VERSION 5.8 ;
BUSBITCHARS "[]" ;
DIVIDERCHAR "/" ;
CLEARANCEMEASURE EUCLIDEAN ;

SITE coresite_DH_P
    SIZE 0.0450 BY 0.2880 ;
    CLASS CORE ;
    SYMMETRY X Y ;
END coresite_DH_P

SITE coresite_DH_N
    SIZE 0.0450 BY 0.2880 ;
    CLASS CORE ;
    SYMMETRY X Y ;
END coresite_DH_N

SITE coresite
    SIZE 0.0450 BY 0.1440 ;
    CLASS CORE ;
    SYMMETRY X Y ;
END coresite

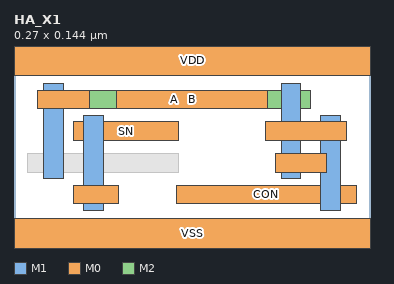
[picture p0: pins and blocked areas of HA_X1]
MACRO HA_X1
  CLASS CORE ;
  ORIGIN 0 0 ;
  FOREIGN HA_X1 0 0 ;
  SIZE 0.2700 BY 0.1440 ;
  SYMMETRY X Y ;
  SITE coresite ;
  PIN SN
    DIRECTION OUTPUT ;
    USE SIGNAL ;
    PORT
      LAYER M1 ;
        RECT 0.0525 0.0960 0.0675 0.0240 ;
      LAYER M0 ;
        RECT 0.0450 0.0430 0.0795 0.0290 ;
        RECT 0.0450 0.0910 0.1245 0.0770 ;
    END
  END SN
  PIN CON
    DIRECTION OUTPUT ;
    USE SIGNAL ;
    PORT
      LAYER M1 ;
        RECT 0.2325 0.0960 0.2475 0.0240 ;
      LAYER M0 ;
        RECT 0.1230 0.0430 0.2595 0.0290 ;
        RECT 0.1905 0.0910 0.2520 0.0770 ;
    END
  END CON
  PIN A
    DIRECTION INPUT ;
    USE SIGNAL ;
    PORT
      LAYER M2 ;
        RECT 0.0180 0.1150 0.2250 0.1010 ;
      LAYER M1 ;
        RECT 0.0225 0.1200 0.0375 0.0480 ;
        RECT 0.2025 0.1200 0.2175 0.0480 ;
      LAYER M0 ;
        RECT 0.0180 0.1150 0.0570 0.1010 ;
        RECT 0.1980 0.0670 0.2370 0.0530 ;
    END
  END A
  PIN B
    DIRECTION INPUT ;
    USE SIGNAL ;
    PORT
      LAYER M0 ;
        RECT 0.0780 0.1150 0.1920 0.1010 ;
    END
  END B
  PIN VDD
    DIRECTION INOUT ;
    USE POWER ;
    SHAPE ABUTMENT ;
    PORT
      LAYER M0 ;
        RECT 0.0000 0.1260 0.2700 0.1620 ;
    END
  END VDD
  PIN VSS
    DIRECTION INOUT ;
    USE GROUND ;
    SHAPE ABUTMENT ;
    PORT
      LAYER M0 ;
        RECT 0.0000 -0.0180 0.2700 0.0180 ;
    END
  END VSS
  OBS
      LAYER V1 ;
        RECT 0.0230 0.1010 0.0370 0.1150 ;
        RECT 0.2030 0.1010 0.2170 0.1150 ;
      LAYER V0 ;
        RECT 0.0530 0.0770 0.0670 0.0910 ;
        RECT 0.0530 0.0290 0.0670 0.0430 ;
        RECT 0.2330 0.0770 0.2470 0.0910 ;
        RECT 0.2330 0.0290 0.2470 0.0430 ;
        RECT 0.0230 0.1010 0.0370 0.1150 ;
        RECT 0.2030 0.0530 0.2170 0.0670 ;
      LAYER M0 ;
        RECT 0.0105 0.0530 0.1245 0.0670 ;
  END
END HA_X1

END LIBRARY
